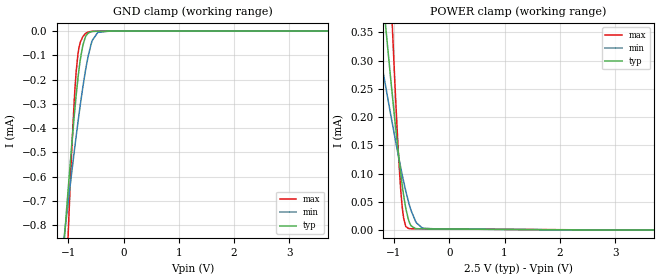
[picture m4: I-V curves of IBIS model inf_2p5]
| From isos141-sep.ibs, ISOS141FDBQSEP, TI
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|   inf_2p5 Model
[Model]   inf_2p5
Model_type   Input
Vinl = 0.75
Vinh = 1.75
|   typ   min   max
|   (nom PVT)   (fast PVT)   (slow PVT)
C_comp   3.281e-15   3.281e-15   3.250e-14
[Model spec]
|subparameter
Vinl   0.75   0.675   0.825
Vinh   1.75   1.575   1.925
| Where nom  PVT is Nominal Process, 2.5V, 27C
|   Fast PVT is Strong Process,  2.75V, -55C
|   Slow PVT is Weak Process,   2.25V, 150C
[Voltage Range]   2.5   2.25   2.75
|Junction Temperature
[Temperature Range]   27   150   -55
[Power Clamp Reference]   2.5   2.25   2.75
[GND Clamp Reference]   0   0   0
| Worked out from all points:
|   GND clamp passes 1 mA (typ) near -1.12 V on its own axis
[GND Clamp]
|   Voltage   I(typ)   I(min)   I(max)
-2.5V     -5.567mA   -3.855mA   -11.2mA
-1.069V   -852.9uA   -838.7uA   -1.235mA
-1.015V   -691.7uA   -732.3uA   -913.4uA
-962.5mV  -540.3uA   -630.7uA   -621.5uA
-880mV    -320.6uA   -475.8uA   -242.7uA
-825mV    -195.8uA   -377.3uA   -96.08uA
-735mV    -57.68uA   -229.6uA   -22.57uA
-641mV    -8.597uA   -105.1uA   -3.988uA
-564mV    -1.717uA   -38.11uA   -871.4nA
-466mV    -415.4nA   -5.597uA   -322nA
-250mV    -166.5nA   -222.7nA   -161.2nA
5V        0A         0A         0A
[POWER Clamp]
|   Voltage   I(typ)   I(min)   I(max)
-2.5V     1.814mA    1.041mA    3.986mA
-1.351V   566.8uA    365.9uA    1.114mA
-1.196V   405.7uA    279uA      742.4uA
-1.053V   260.5uA    200.3uA    408.8uA
-990.2mV  199.2uA    166.7uA    271uA
-924.3mV  138.4uA    132.7uA    141.2uA
-874.8mV  96.55uA    108.3uA    65.49uA
-822.5mV  58.5uA     83.91uA    18.88uA
-740mV    18.48uA    50.19uA    2.683uA
-612.5mV  2.435uA    15.71uA    2.168uA
-486.3mV  1.99uA     3.311uA    2.086uA
5V        0A         0A         0A
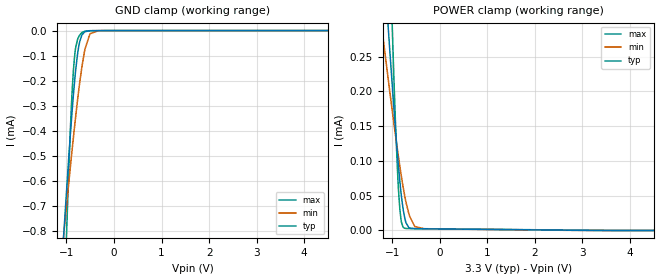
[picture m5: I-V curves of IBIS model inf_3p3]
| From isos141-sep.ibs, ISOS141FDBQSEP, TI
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|   inf_3p3 Model
[Model]   inf_3p3
Model_type   Input
Vinl = 0.99
Vinh = 2.31
|   typ   min   max
|   (nom PVT)   (fast PVT)   (slow PVT)
C_comp   3.281e-15   3.281e-15   3.329e-14
[Model spec]
|subparameter
Vinl   0.99   0.891   1.089
Vinh   2.31   2.079   2.541
| Where nom  PVT is Nominal Process, 3.3V, 27C
|   Fast PVT is Strong Process,  3.63V, -55C
|   Slow PVT is Weak Process,   2.97V, 150C
[Voltage Range]   3.3   2.97   3.63
|Junction Temperature
[Temperature Range]   27   150   -55
[Power Clamp Reference]   3.3   2.97   3.63
[GND Clamp Reference]   0   0   0
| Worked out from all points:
|   GND clamp passes 1 mA (typ) near -1.12 V on its own axis
|   POWER clamp passes 1 mA (typ) near -1.75 V on its own axis
[GND Clamp]
|   Voltage   I(typ)   I(min)   I(max)
-3.3V     -8.284mA   -5.57mA    -16.97mA
-1.076V   -873.6uA   -852.3uA   -1.277mA
-1.002V   -654.2uA   -707.4uA   -840.1uA
-891.3mV  -349uA     -496.6uA   -285.5uA
-853.4mV  -257.3uA   -427.5uA   -158.6uA
-821.7mV  -189.1uA   -371.5uA   -90.58uA
-768.9mV  -98.39uA   -282.7uA   -37.63uA
-719.4mV  -43.62uA   -206.4uA   -17.63uA
-617.1mV  -5.129uA   -80.39uA   -2.416uA
-505.2mV  -641.2nA   -12.81uA   -412.3nA
-330mV    -221.3nA   -470.3nA   -212.8nA
6.6V      0A         0A         0A
[POWER Clamp]
|   Voltage   I(typ)   I(min)   I(max)
-3.3V     2.696mA    1.52mA     6.012mA
-1.242V   453.3uA    304.9uA    851.4uA
-1.198V   407.7uA    280.3uA    746.3uA
-1.049V   257.2uA    198.7uA    400.8uA
-965.9mV  176.8uA    154.6uA    221.3uA
-878.8mV  100.3uA    110.8uA    71.18uA
-842.5mV  72.63uA    93.56uA    33uA
-805.2mV  48.41uA    76.82uA    11.74uA
-737.2mV  18.14uA    49.73uA    3.193uA
-526mV    2.561uA    5.724uA    2.679uA
-330mV    2.416uA    2.488uA    2.553uA
6.6V      0A         0A         0A
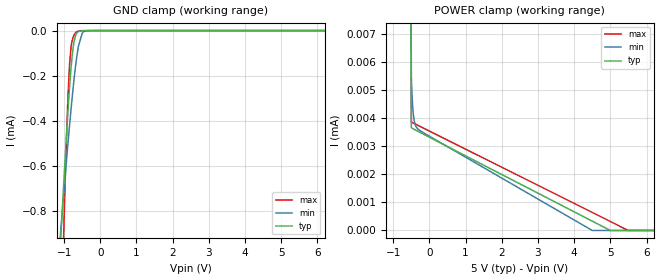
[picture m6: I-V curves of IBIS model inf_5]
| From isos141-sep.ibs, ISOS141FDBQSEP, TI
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|   inf_5 Model
[Model]   inf_5
Model_type   Input
Vinl = 1.5
Vinh = 3.5
|   typ   min   max
|   (nom PVT)   (fast PVT)   (slow PVT)
C_comp   3.281e-15   3.281e-15   3.455e-14
[Model spec]
|subparameter
Vinl   1.5   1.35   1.65
Vinh   3.5   3.15   3.85
| Where nom  PVT is Nominal Process, 5V, 27C
|   Fast PVT is Strong Process,  5.5V, -55C
|   Slow PVT is Weak Process,   4.5V, 150C
[Voltage Range]   5   4.5   5.5
|Junction Temperature
[Temperature Range]   27   150   -55
[Power Clamp Reference]   5   4.5   5.5
[GND Clamp Reference]   0   0   0
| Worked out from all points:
|   GND clamp passes 1 mA (typ) near -1.12 V on its own axis
[GND Clamp]
|   Voltage   I(typ)   I(min)   I(max)
-5V       -13.99mA   -9.044mA   -29.25mA
-1.112V   -984.3uA   -924.5uA   -1.502mA
-1.062V   -831.8uA   -824.9uA   -1.192mA
-974mV    -572.9uA   -652.8uA   -683.2uA
-908mV    -391.9uA   -527.5uA   -354.9uA
-850mV    -249.6uA   -421.5uA   -149.8uA
-809mV    -164.5uA   -349.6uA   -72.24uA
-740mV    -62.8uA    -237.2uA   -24.38uA
-608mV    -4.229uA   -71.85uA   -2.005uA
-500mV    -598.4nA   -11.5uA    -395.2nA
-347mV    -233.9nA   -591nA     -223.9nA
10V       0A         0A         0A
[POWER Clamp]
|   Voltage   I(typ)   I(min)   I(max)
-5V       185.5mA    66.86mA    305.6mA
-1.007V   217uA      177.2uA    308.5uA
-500mV    3.667uA    5.488uA    3.869uA
-486.5mV  3.656uA    5.003uA    3.86uA
-468.5mV  3.642uA    4.538uA    3.848uA
-428mV    3.613uA    3.98uA     3.822uA
-374mV    3.577uA    3.716uA    3.787uA
-279.5mV  3.514uA    3.578uA    3.726uA
4.5V      333.1nA    0A         645nA
5.005V    0A         0A         319.1nA
5.49V     0A         0A         0A
10V       0A         0A         0A
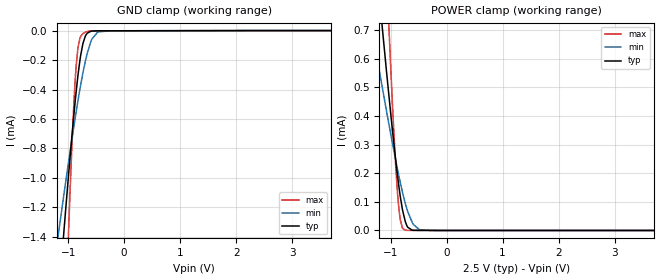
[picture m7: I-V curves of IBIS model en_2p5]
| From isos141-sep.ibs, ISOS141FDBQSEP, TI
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|   en_2p5 Model
[Model]   en_2p5
Model_type   Input
Vinl = 0.75
Vinh = 1.75
|   typ   min   max
|   (nom PVT)   (fast PVT)   (slow PVT)
C_comp   3.303e-15   3.281e-15   1.151e-13
[Model spec]
|subparameter
Vinl   0.75   0.675   0.825
Vinh   1.75   1.575   1.925
| Where nom  PVT is Nominal Process, 2.5V, 27C
|   Fast PVT is Strong Process,  2.75V, -55C
|   Slow PVT is Weak Process,   2.25V, 150C
[Voltage Range]   2.5   2.25   2.75
|Ambient Temperature   25   125   -55
|Junction Temperature
[Temperature Range]   27   150   -55
[Power Clamp Reference]   2.5   2.25   2.75
[GND Clamp Reference]   0   0   0
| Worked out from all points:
|   GND clamp passes 1 mA (typ) near -1.00 V on its own axis
|   POWER clamp passes 1 mA (typ) near -1.29 V on its own axis
[GND Clamp]
|   Voltage   I(typ)   I(min)   I(max)
-2.5V     -8.647mA   -5.195mA   -19.82mA
-1.224V   -2.083mA   -1.519mA   -3.979mA
-1.065V   -1.316mA   -1.086mA   -2.148mA
-1.001V   -1.021mA   -917uA     -1.46mA
-891.2mV  -548.7uA   -636.9uA   -451.9uA
-857.5mV  -419.8uA   -554.9uA   -246.1uA
-825.3mV  -308.5uA   -479.2uA   -120.6uA
-789.5mV  -203.1uA   -398.8uA   -52.86uA
-691mV    -36.17uA   -205.8uA   -10.4uA
-575mV    -3.575uA   -57.61uA   -2.24uA
-250mV    -1.373uA   -1.462uA   -1.451uA
5V        0A         0A         0A
[POWER Clamp]
|   Voltage   I(typ)   I(min)   I(max)
-2.5V     3.622mA    2.076mA    7.967mA
-1.351V   1.129mA    727.2uA    2.224mA
-1.196V   807.1uA    553.5uA    1.48mA
-1.053V   516.7uA    396.2uA    813.3uA
-990.2mV  394.3uA    329.2uA    537.7uA
-924.3mV  272.7uA    261.2uA    278.2uA
-874.8mV  189uA      212.4uA    126.7uA
-822.5mV  113uA      163.7uA    33.56uA
-740mV    33.03uA    96.34uA    1.225uA
-612.5mV  1.036uA    27.5uA     297.8nA
-486.3mV  250nA      2.81uA     235.3nA
5V        0A         0A         0A
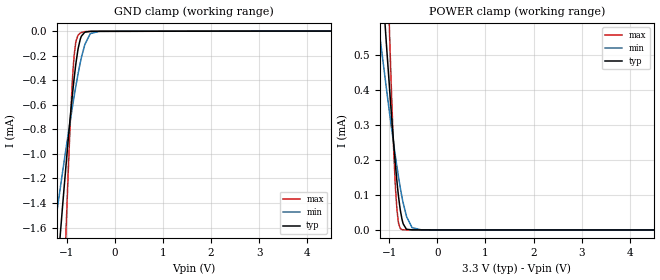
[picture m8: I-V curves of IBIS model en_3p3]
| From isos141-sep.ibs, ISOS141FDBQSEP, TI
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|   en_3p3 Model
[Model]   en_3p3
Model_type   Input
Vinl = 0.99
Vinh = 2.31
|   typ   min   max
|   (nom PVT)   (fast PVT)   (slow PVT)
C_comp   3.303e-15   3.281e-15   1.158e-13
[Model spec]
|subparameter
Vinl   0.99   0.891   1.089
Vinh   2.31   2.079   2.541
| Where nom  PVT is Nominal Process, 3.3V, 27C
|   Fast PVT is Strong Process,  3.63V, -55C
|   Slow PVT is Weak Process,   2.97V, 150C
[Voltage Range]   3.3   2.97   3.63
|Ambient Temperature   25   125   -55
|Junction Temperature
[Temperature Range]   27   150   -55
[Power Clamp Reference]   3.3   2.97   3.63
[GND Clamp Reference]   0   0   0
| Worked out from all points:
|   GND clamp passes 1 mA (typ) near -1.00 V on its own axis
|   POWER clamp passes 1 mA (typ) near -1.29 V on its own axis
[GND Clamp]
|   Voltage   I(typ)   I(min)   I(max)
-3.3V     -12.85mA   -7.552mA   -29.96mA
-1.251V   -2.215mA   -1.593mA   -4.295mA
-1.213V   -2.028mA   -1.488mA   -3.846mA
-1.063V   -1.305mA   -1.079mA   -2.122mA
-980.4mV  -927.6uA   -862.8uA   -1.246mA
-926mV    -691uA     -723.5uA   -729.1uA
-849.8mV  -392.1uA   -536.5uA   -209.7uA
-808.2mV  -255.7uA   -440.3uA   -80.89uA
-697.3mV  -41.71uA   -216.6uA   -11.76uA
-511.2mV  -2.293uA   -20.49uA   -2.098uA
-330mV    -1.815uA   -2.199uA   -1.916uA
6.6V      0A         0A         0A
[POWER Clamp]
|   Voltage   I(typ)   I(min)   I(max)
-3.3V     5.384mA    3.032mA    12.02mA
-1.242V   901.1uA    604.2uA    1.697mA
-1.198V   810uA      555uA      1.487mA
-1.049V   509.1uA    392uA      796uA
-965.9mV  348.5uA    303.8uA    437.1uA
-878.8mV  195.5uA    216.3uA    137uA
-842.5mV  140.2uA    181.9uA    60.64uA
-805.2mV  91.77uA    148.5uA    18.16uA
-737.2mV  31.27uA    94.34uA    1.112uA
-526mV    293.6nA    6.522uA    254.6nA
-330mV    164.9nA    232nA      159.7nA
6.6V      0A         0A         0A
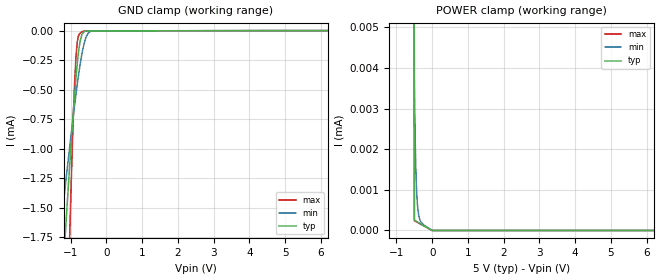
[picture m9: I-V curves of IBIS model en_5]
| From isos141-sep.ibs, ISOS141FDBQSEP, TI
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|   en_5 Model
[Model]   en_5
Model_type   Input
Vinl = 1.5
Vinh = 3.5
|   typ   min   max
|   (nom PVT)   (fast PVT)   (slow PVT)
C_comp   3.303e-15   3.281e-15   1.164e-13
[Model spec]
|subparameter
Vinl   1.5   1.35   1.65
Vinh   3.5   3.15   3.85
| Where nom  PVT is Nominal Process, 5V, 27C
|   Fast PVT is Strong Process,  5.5V, -55C
|   Slow PVT is Weak Process,   4.5V, 150C
[Voltage Range]   5   4.5   5.5
|Ambient Temperature   25   125   -55
|Junction Temperature
[Temperature Range]   27   150   -55
[Power Clamp Reference]   5   4.5   5.5
[GND Clamp Reference]   0   0   0
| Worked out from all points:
|   GND clamp passes 1 mA (typ) near -1.00 V on its own axis
[GND Clamp]
|   Voltage   I(typ)   I(min)   I(max)
-5V       -21.84mA   -12.59mA   -51.61mA
-1.304V   -2.48mA    -1.741mA   -4.932mA
-1.155V   -1.749mA   -1.331mA   -3.177mA
-1.128V   -1.616mA   -1.256mA   -2.86mA
-1.029V   -1.148mA   -990.1uA   -1.755mA
-927.5mV  -697.6uA   -727.4uA   -742.8uA
-855mV    -411.2uA   -549.1uA   -234.7uA
-790mV    -205uA     -400.1uA   -54.24uA
-685mV    -32.64uA   -196.1uA   -10.51uA
-567.5mV  -4.417uA   -52.27uA   -3.419uA
-369.5mV  -2.688uA   -3.564uA   -2.84uA
10V       0A         0A         0A
[POWER Clamp]
|   Voltage   I(typ)   I(min)   I(max)
-5V       371.1mA    133.7mA    611.2mA
-1.007V   426.4uA    346.8uA    609.2uA
-500mV    261.7nA    3.784uA    242nA
-491mV    253.9nA    3.115uA    237.6nA
-482mV    247nA      2.562uA    233.3nA
-473mV    240.7nA    2.107uA    228.9nA
-460mV    232.6nA    1.595uA    222.6nA
-432.5mV  217.1nA    909.5nA    209.3nA
-392mV    196.1nA    454.6nA    189.8nA
-306.5mV  153.2nA    197.5nA    148.4nA
-500uV    0A         0A         0A
10V       0A         0A         0A
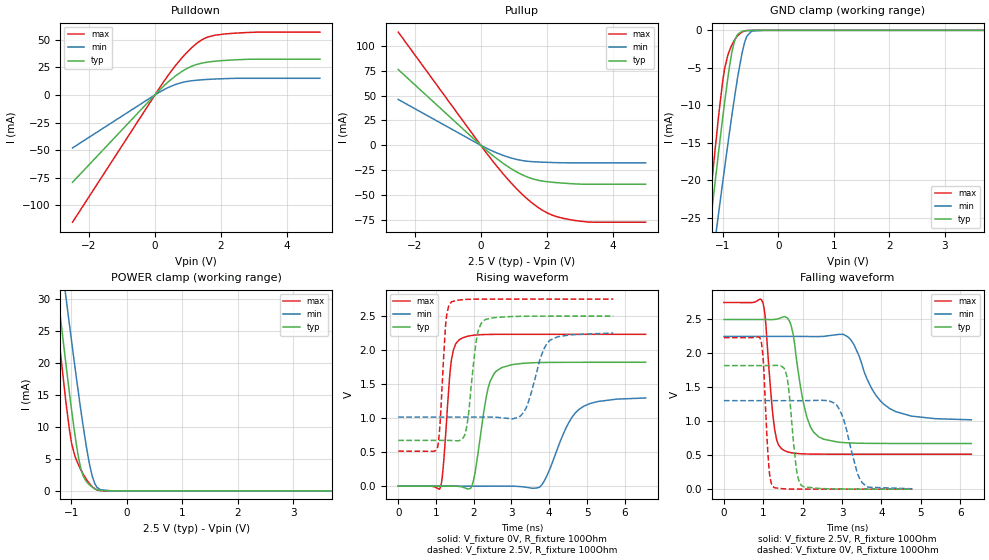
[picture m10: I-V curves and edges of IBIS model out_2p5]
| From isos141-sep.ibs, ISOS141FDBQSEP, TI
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|   out_2p5 Model
[Model]   out_2p5
Model_type   3-state
Polarity   Inverting
Vmeas = 1.25
Vref = 0
Cref = 15pF
Rref = 100
|   typ   min   max
|   (nom PVT)   (fast PVT)   (slow PVT)
C_comp   1.027e-12   9.377e-13   1.105e-12
| Where nom  PVT is Nominal Process, 2.5V, 27C
|   Fast PVT is Strong Process,  2.75V, -55C
|   Slow PVT is Weak Process,   2.25V, 150C
[Voltage Range]   2.5   2.25   2.75
|Ambient Temperature   25   125   -55
|Junction Temperature
[Temperature Range]   27   150   -55
[Pullup Reference]   2.5   2.25   2.75
[Pulldown Reference]   0   0   0
[Power Clamp Reference]   2.5   2.25   2.75
[GND Clamp Reference]   0   0   0
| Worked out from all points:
|   slope of the pulldown table from 0 to 0.375 V, typ, clamps not added: 34 ohm
|   slope of the pullup table from 0 to 0.375 V, typ, clamps not added: 35.4 ohm
|   GND clamp passes 1 mA (typ) near -0.76 V on its own axis
|   POWER clamp passes 1 mA (typ) near -0.68 V on its own axis
|   falling waveform, V_fixture 2.5V, R_fixture 100Ohm: 20-80 % time 324ps typ, 633ps min, 191ps max; typ from 2.5 V to 0.673 V
|   rising waveform, V_fixture 0V, R_fixture 100Ohm: 20-80 % time 307ps typ, 615ps min, 178ps max; typ from 0 V to 1.82 V
|   rising waveform, V_fixture 2.5V, R_fixture 100Ohm: 20-80 % time 210ps typ, 390ps min, 134ps max; typ from 0.673 V to 2.5 V
|   falling waveform, V_fixture 0V, R_fixture 100Ohm: 20-80 % time 178ps typ, 345ps min, 117ps max; typ from 1.82 V to 0 V
[Pulldown]
|   Voltage   I(typ)   I(min)   I(max)
-2.5V     -79.05mA   -47.97mA   -115.1mA
242.5mV   7.369mA    4.254mA    10.99mA
604.8mV   16.75mA    9.164mA    25.83mA
786.3mV   20.6mA     10.9mA     32.43mA
1.1V      25.7mA     12.7mA     42.29mA
1.292V    27.74mA    13.31mA    47.16mA
1.408V    28.6mA     13.59mA    49.53mA
1.631V    29.75mA    14.02mA    52.54mA
2.148V    31.19mA    14.7mA     55.16mA
3.105V    32.21mA    14.98mA    56.72mA
5V        32.21mA    14.98mA    56.75mA
[GND Clamp]
|   Voltage   I(typ)   I(min)   I(max)
-2.5V     -113.8mA   -109.3mA   -126.7mA
-1.327V   -32.82mA   -39.06mA   -30.54mA
-1.16V    -21.76mA   -29.34mA   -17.63mA
-1.073V   -16.17mA   -24.36mA   -11.36mA
-960mV    -9.309mA   -18.06mA   -4.938mA
-871mV    -4.546mA   -13.26mA   -2.575mA
-805mV    -1.936mA   -9.853mA   -1.543mA
-742.5mV  -678.4uA   -6.825mA   -835.1uA
-655mV    -148uA     -3.167mA   -231.5uA
-565mV    -24.88uA   -787.3uA   -32.49uA
-475mV    -3.219uA   -94.87uA   -2.89uA
5V        0A         0A         0A
[Pullup]
|   Voltage   I(typ)   I(min)   I(max)
-2.5V     76.08mA    46.03mA    113.8mA
0V        0A         0A         0A
350.8mV   -9.946mA   -5.734mA   -15.38mA
665mV     -17.88mA   -10.02mA   -28.2mA
1.061V    -26.29mA   -14.04mA   -42.81mA
1.343V    -30.95mA   -15.79mA   -51.94mA
1.605V    -34.09mA   -16.59mA   -59.28mA
1.905V    -36.18mA   -17.06mA   -66.05mA
2.148V    -37.13mA   -17.34mA   -70mA
2.754V    -38.65mA   -17.71mA   -75.11mA
3.3V      -39.22mA   -17.71mA   -77.31mA
5V        -39.22mA   -17.71mA   -77.36mA
[POWER Clamp]
|   Voltage   I(typ)   I(min)   I(max)
-2.5V     130.5mA    131.5mA    137.5mA
-1.331V   37.45mA    46.69mA    32.98mA
-1.194V   27mA       37.02mA    21.48mA
-1.096V   19.79mA    30.25mA    13.84mA
-984.8mV  12.01mA    22.71mA    7.082mA
-912.5mV  7.491mA    17.96mA    4.93mA
-833.5mV  3.695mA    12.97mA    3.404mA
-782.5mV  2.286mA    9.916mA    2.578mA
-667.5mV  905.1uA    3.994mA    1.088mA
-539.3mV  198.3uA    596.8uA    170.5uA
-250mV    142.1nA    1.582uA    12.72nA
5V        0A         0A         0A
[Ramp]
R_load = 100
|   typ   min   max
dV/dt_r   1.0926/3.05799e-10   0.781809/6.18175e-10   1.33922/1.76792e-10
dV/dt_f   1.09612/3.21737e-10   0.740101/6.33785e-10   1.34089/1.89159e-10
[Falling Waveform]
V_fixture = 2.5V
V_fixture_min = 2.25V
V_fixture_max = 2.75V
R_fixture = 100Ohm
|   Time   V(typ)   V(min)   V(max)
0s        2.5V       2.25V      2.75V
980ps     2.5V       2.25V      2.76V
1.286ns   2.501V     2.25V      890.3mV
1.528ns   2.543V     2.25V      570.3mV
1.718ns   2.385V     2.25V      536.1mV
2.106ns   1.061V     2.25V      518.2mV
2.4ns     774.3mV    2.249V     515.8mV
3.212ns   680.8mV    2.208V     515.2mV
4.206ns   673.5mV    1.189V     515.2mV
6.284ns   673.1mV    1.022V     515.2mV
[Rising Waveform]
V_fixture = 0V
V_fixture_min = 0V
V_fixture_max = 0V
R_fixture = 100Ohm
|   Time   V(typ)   V(min)   V(max)
0s        2.759nV    92.09nV    1.558nV
1.108ns   -49.93uV   25.48nV    -28.41mV
1.41ns    984.8uV    875.7nV    1.858V
1.61ns    -3.002mV   3.634uV    2.149V
1.962ns   21.52mV    -16.69uV   2.216V
2.34ns    1.338V     -18.47uV   2.229V
2.596ns   1.691V     495.7uV    2.231V
3.742ns   1.817V     -15.19mV   2.232V
4.912ns   1.821V     1.175V     2.232V
6.554ns   1.821V     1.297V     2.232V
[Rising Waveform]
V_fixture = 2.5V
V_fixture_min = 2.25V
V_fixture_max = 2.75V
R_fixture = 100Ohm
|   Time   V(typ)   V(min)   V(max)
0s        673.1mV    1.016V     515.1mV
1.042ns   673.1mV    1.016V     569.3mV
1.262ns   673.3mV    1.016V     2.408V
1.414ns   671.2mV    1.016V     2.711V
1.786ns   800.7mV    1.016V     2.744V
2.074ns   2.166V     1.016V     2.749V
2.23ns    2.416V     1.016V     2.749V
3.266ns   2.497V     1.048V     2.75V
4.012ns   2.5V       2.143V     2.75V
5.698ns   2.5V       2.25V      2.75V
[Falling Waveform]
V_fixture = 0V
V_fixture_min = 0V
V_fixture_max = 0V
R_fixture = 100Ohm
|   Time   V(typ)   V(min)   V(max)
0s        1.821V     1.304V     2.232V
936ps     1.821V     1.304V     2.195V
1.146ns   1.821V     1.304V     295.8mV
1.23ns    1.822V     1.304V     45.6mV
1.606ns   1.645V     1.304V     3.087mV
1.84ns    296.4mV    1.304V     656.2uV
1.97ns    52.25mV    1.304V     261.7uV
2.862ns   3.154mV    1.24V      -4.6uV
3.606ns   514.4uV    47.67mV    -72.66nV
4.784ns   44.2uV     5.601mV    2.782nV
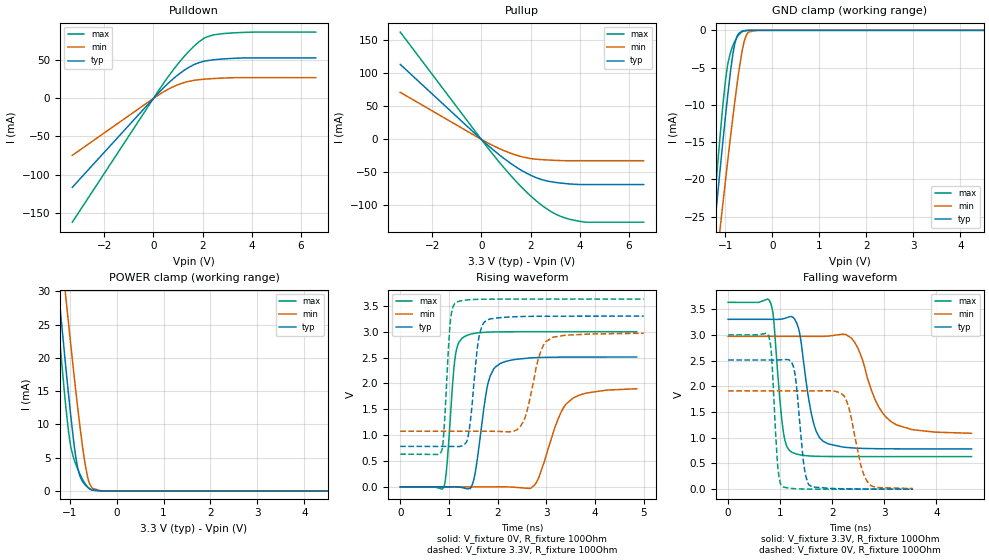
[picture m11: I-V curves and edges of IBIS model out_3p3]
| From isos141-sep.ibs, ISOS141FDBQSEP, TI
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|   out_3p3 Model
[Model]   out_3p3
Model_type   3-state
Polarity   Inverting
Vmeas = 1.65
Vref = 0
Cref = 15pF
Rref = 100
|   typ   min   max
|   (nom PVT)   (fast PVT)   (slow PVT)
C_comp   9.270e-13   8.382e-13   1.039e-12
| Where nom  PVT is Nominal Process, 3.3V, 27C
|   Fast PVT is Strong Process,  3.63V, -55C
|   Slow PVT is Weak Process,   2.97V, 150C
[Voltage Range]   3.3   2.97   3.63
|Ambient Temperature   25   125   -55
|Junction Temperature
[Temperature Range]   27   150   -55
[Pullup Reference]   3.3   2.97   3.63
[Pulldown Reference]   0   0   0
[Power Clamp Reference]   3.3   2.97   3.63
[GND Clamp Reference]   0   0   0
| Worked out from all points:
|   slope of the pulldown table from 0 to 0.495 V, typ, clamps not added: 29.7 ohm
|   slope of the pullup table from 0 to 0.495 V, typ, clamps not added: 30.6 ohm
|   GND clamp passes 1 mA (typ) near -0.76 V on its own axis
|   POWER clamp passes 1 mA (typ) near -0.68 V on its own axis
|   falling waveform, V_fixture 3.3V, R_fixture 100Ohm: 20-80 % time 230ps typ, 430ps min, 149ps max; typ from 3.3 V to 0.782 V
|   rising waveform, V_fixture 0V, R_fixture 100Ohm: 20-80 % time 227ps typ, 427ps min, 140ps max; typ from 0 V to 2.51 V
|   rising waveform, V_fixture 3.3V, R_fixture 100Ohm: 20-80 % time 157ps typ, 277ps min, 107ps max; typ from 0.782 V to 3.3 V
|   falling waveform, V_fixture 0V, R_fixture 100Ohm: 20-80 % time 138ps typ, 238ps min, 95.1ps max; typ from 2.51 V to 0 V
[Pulldown]
|   Voltage   I(typ)   I(min)   I(max)
-3.3V     -116.8mA   -74.8mA    -162.6mA
67.98mV   2.426mA    1.528mA    3.39mA
463mV     15.67mA    9.587mA    22.3mA
860mV     27.32mA    16.13mA    39.76mA
1.256V    37mA       20.88mA    55.31mA
1.633V    44.06mA    23.59mA    68.06mA
1.858V    47.02mA    24.56mA    74.44mA
2.123V    49.2mA     25.37mA    80.1mA
2.414V    50.61mA    26.01mA    83.21mA
2.867V    51.88mA    26.71mA    85.18mA
3.97V     53.09mA    27.18mA    86.97mA
6.6V      53.09mA    27.18mA    87.05mA
[GND Clamp]
|   Voltage   I(typ)   I(min)   I(max)
-3.3V     -170.3mA   -157.8mA   -194.4mA
-1.317V   -32.1mA    -38.42mA   -29.69mA
-1.236V   -26.73mA   -33.72mA   -23.39mA
-1.158V   -21.65mA   -29.24mA   -17.5mA
-1.073V   -16.16mA   -24.35mA   -11.34mA
-953.7mV  -8.946mA   -17.72mA   -4.696mA
-879.4mV  -4.954mA   -13.71mA   -2.735mA
-798.6mV  -1.751mA   -9.533mA   -1.459mA
-656.7mV  -152.7uA   -3.229mA   -238.9uA
-558.7mV  -21.74uA   -692.2uA   -27.8uA
-330mV    -65.89nA   -2.179uA   -17.08nA
6.6V      0A         0A         0A
[Pullup]
|   Voltage   I(typ)   I(min)   I(max)
-3.3V     113.7mA    71.42mA    162.6mA
0V        0A         0A         0A
742.2mV   -23.69mA   -14.11mA   -35.04mA
1.223V    -37.05mA   -21.36mA   -55.86mA
1.648V    -47.2mA    -26.21mA   -72.73mA
2.043V    -54.93mA   -29.12mA   -86.88mA
2.406V    -60.25mA   -30.47mA   -98.28mA
2.824V    -63.99mA   -31.34mA   -109.1mA
3.209V    -65.98mA   -31.95mA   -116.3mA
3.994V    -68.26mA   -32.19mA   -124mA
4.279V    -68.26mA   -32.19mA   -125.3mA
6.6V      -68.26mA   -32.19mA   -125.3mA
[POWER Clamp]
|   Voltage   I(typ)   I(min)   I(max)
-3.3V     196.1mA    190mA      211.9mA
-1.367V   40.17mA    49.19mA    36mA
-1.274V   33.06mA    42.63mA    28.11mA
-1.198V   27.34mA    37.33mA    21.84mA
-1.081V   18.74mA    29.25mA    12.78mA
-973.2mV  11.25mA    21.94mA    6.628mA
-891mV    6.299mA    16.58mA    4.476mA
-825mV    3.399mA    12.45mA    3.258mA
-668.6mV  913.7uA    4.04mA     1.1mA
-592mV    415.6uA    1.476mA    435.3uA
-517.1mV  136.9uA    396.6uA    105.4uA
6.6V      0A         0A         0A
[Ramp]
R_load = 100
|   typ   min   max
dV/dt_r   1.50593/2.2717e-10   1.14438/4.28829e-10   1.79944/1.38256e-10
dV/dt_f   1.51075/2.29121e-10   1.13588/4.29308e-10   1.79824/1.48959e-10
[Falling Waveform]
V_fixture = 3.3V
V_fixture_min = 2.97V
V_fixture_max = 3.63V
R_fixture = 100Ohm
|   Time   V(typ)   V(min)   V(max)
0s        3.3V       2.97V      3.63V
810ps     3.3V       2.97V      3.632V
1.06ns    3.312V     2.97V      1.113V
1.212ns   3.355V     2.97V      725.4mV
1.374ns   3.028V     2.97V      667.8mV
1.642ns   1.272V     2.969V     641.1mV
1.828ns   929.1mV    2.97V      636.1mV
2.428ns   799.2mV    2.857V     633.1mV
3.126ns   784mV      1.314V     633mV
4.674ns   782.1mV    1.085V     632.9mV
[Rising Waveform]
V_fixture = 0V
V_fixture_min = 0V
V_fixture_max = 0V
R_fixture = 100Ohm
|   Time   V(typ)   V(min)   V(max)
0s        3.012nV    81.93nV    1.808nV
902ps     -33.98uV   -43.22nV   5.841mV
1.126ns   1.417mV    2.088uV    2.494V
1.272ns   -13.51mV   4.888uV    2.875V
1.512ns   139.9mV    -29.36uV   2.964V
1.788ns   1.938V     73.47uV    2.99V
1.956ns   2.318V     808.3uV    2.995V
2.754ns   2.497V     31.25mV    2.999V
3.548ns   2.509V     1.715V     2.999V
4.858ns   2.51V      1.897V     2.999V
[Rising Waveform]
V_fixture = 3.3V
V_fixture_min = 2.97V
V_fixture_max = 3.63V
R_fixture = 100Ohm
|   Time   V(typ)   V(min)   V(max)
0s        782mV      1.075V     632.8mV
852ps     782mV      1.075V     699.9mV
1.03ns    782.2mV    1.075V     3.204V
1.164ns   779.9mV    1.075V     3.574V
1.376ns   905.9mV    1.075V     3.613V
1.608ns   2.848V     1.075V     3.625V
1.772ns   3.22V      1.076V     3.628V
2.464ns   3.292V     1.163V     3.63V
3.138ns   3.299V     2.893V     3.63V
5ns       3.3V       2.969V     3.63V
[Falling Waveform]
V_fixture = 0V
V_fixture_min = 0V
V_fixture_max = 0V
R_fixture = 100Ohm
|   Time   V(typ)   V(min)   V(max)
0s        2.51V      1.91V      2.999V
778ps     2.51V      1.91V      2.976V
836ps     2.509V     1.91V      2.555V
954ps     2.51V      1.91V      427.5mV
1.05ns    2.516V     1.91V      44.04mV
1.264ns   2.344V     1.91V      10.22mV
1.556ns   77.23mV    1.909V     1.359mV
2.248ns   6.809mV    1.776V     11.19uV
2.716ns   1.984mV    90.24mV    1.563uV
3.55ns    306.8uV    11.74mV    72.61nV
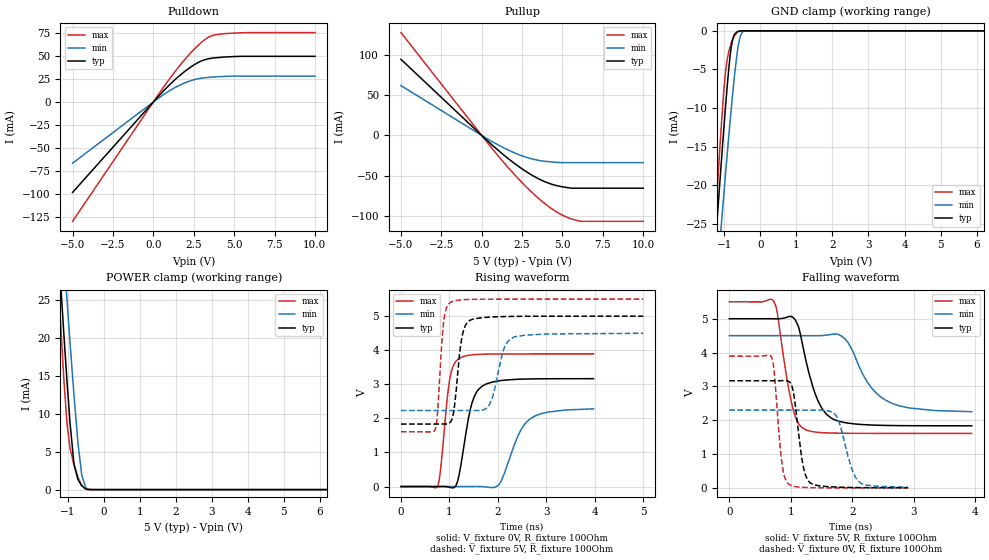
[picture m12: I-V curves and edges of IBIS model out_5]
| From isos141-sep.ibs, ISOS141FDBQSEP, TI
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|   out_5 Model
[Model]   out_5
Model_type   3-state
Polarity   Inverting
Vmeas = 2.5
Vref = 0
Cref = 15pF
Rref = 150
|   typ   min   max
|   (nom PVT)   (fast PVT)   (slow PVT)
C_comp   9.635e-13   9.413e-13   9.787e-13
| Where nom  PVT is Nominal Process, 5V, 27C
|   Fast PVT is Strong Process,  5.5V, -55C
|   Slow PVT is Weak Process,   4.5V, 150C
[Voltage Range]   5   4.5   5.5
|Ambient Temperature   25   125   -55
|Junction Temperature
[Temperature Range]   27   150   -55
[Pullup Reference]   5   4.5   5.5
[Pulldown Reference]   0   0   0
[Power Clamp Reference]   5   4.5   5.5
[GND Clamp Reference]   0   0   0
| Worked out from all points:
|   slope of the pulldown table from 0 to 0.75 V, typ, clamps not added: 52.8 ohm
|   slope of the pullup table from 0 to 0.75 V, typ, clamps not added: 54.8 ohm
|   GND clamp passes 1 mA (typ) near -0.76 V on its own axis
|   POWER clamp passes 1 mA (typ) near -0.67 V on its own axis
|   falling waveform, V_fixture 5V, R_fixture 100Ohm: 20-80 % time 296ps typ, 450ps min, 213ps max; typ from 5 V to 1.83 V
|   rising waveform, V_fixture 0V, R_fixture 100Ohm: 20-80 % time 248ps typ, 401ps min, 165ps max; typ from 0 V to 3.17 V
|   rising waveform, V_fixture 5V, R_fixture 100Ohm: 20-80 % time 143ps typ, 225ps min, 108ps max; typ from 1.83 V to 5 V
|   falling waveform, V_fixture 0V, R_fixture 100Ohm: 20-80 % time 137ps typ, 209ps min, 108ps max; typ from 3.17 V to 0.001 V
[Pulldown]
|   Voltage   I(typ)   I(min)   I(max)
-5V       -97.96mA   -66.29mA   -129.3mA
700mV     13.33mA    8.861mA    17.83mA
1.3V      23.59mA    15.28mA    32.05mA
1.97V     33.54mA    20.95mA    46.53mA
2.663V    41.75mA    24.82mA    59.55mA
3.096V    45.35mA    26.09mA    66.4mA
3.591V    47.4mA     26.94mA    71.64mA
4.416V    48.75mA    27.74mA    74.07mA
5.912V    49.52mA    28.03mA    75.26mA
10V       49.52mA    28.03mA    75.26mA
[GND Clamp]
|   Voltage   I(typ)   I(min)   I(max)
-5V       -291.7mA   -259.7mA   -341.9mA
-1.469V   -42.36mA   -47.38mA   -41.81mA
-1.2V     -24.34mA   -31.61mA   -20.61mA
-1.101V   -17.93mA   -25.94mA   -13.29mA
-1.026V   -13.29mA   -21.76mA   -8.356mA
-940mV    -8.166mA   -16.97mA   -4.222mA
-810.5mV  -2.106mA   -10.13mA   -1.616mA
-737.5mV  -623.1uA   -6.594mA   -788.2uA
-638.5mV  -109.1uA   -2.6mA     -169uA
-558.5mV  -21.67uA   -689.5uA   -27.72uA
-387.5mV  -336nA     -9.718uA   -155.2nA
10V       0A         0A         0A
[Pullup]
|   Voltage   I(typ)   I(min)   I(max)
-5V       94.16mA    61.66mA    127.2mA
100mV     -1.88mA    -1.233mA   -2.555mA
1.3V      -23.12mA   -14.74mA   -31.91mA
2.753V    -44.75mA   -26.97mA   -63.54mA
3.883V    -57.04mA   -31.9mA    -83.94mA
4.338V    -60.4mA    -32.77mA   -90.72mA
4.935V    -63.28mA   -33.6mA    -97.99mA
5.49V     -64.99mA   -33.6mA    -102.8mA
5.984V    -65.24mA   -33.6mA    -105.5mA
10V       -65.24mA   -33.6mA    -106.2mA
[POWER Clamp]
|   Voltage   I(typ)   I(min)   I(max)
-5V       516mA      373mA      669.1mA
-1.535V   53.28mA    61.23mA    50.65mA
-1.128V   22.12mA    32.46mA    16.25mA
-1.101V   20.12mA    30.56mA    14.17mA
-1.018V   14.26mA    24.94mA    8.698mA
-935.5mV  8.857mA    19.46mA    5.475mA
-825mV    3.399mA    12.45mA    3.258mA
-710mV    1.283mA    5.971mA    1.578mA
-608mV    501.8uA    1.883mA    547.9uA
-500mV    100.1uA    287.4uA    70.26uA
-260mV    196.4nA    1.991uA    20.04nA
10V       0A         0A         0A
[Ramp]
R_load = 100
|   typ   min   max
dV/dt_r   1.89956/2.4599e-10   1.37645/4.04325e-10   2.33583/1.64321e-10
dV/dt_f   1.89916/2.94487e-10   1.35805/4.5544e-10   2.3339/2.12977e-10
[Falling Waveform]
V_fixture = 5V
V_fixture_min = 4.5V
V_fixture_max = 5.5V
R_fixture = 100Ohm
|   Time   V(typ)   V(min)   V(max)
0s        5V         4.5V       5.5V
728ps     4.998V     4.5V       5.502V
1.034ns   5.042V     4.5V       2.353V
1.244ns   3.792V     4.499V     1.717V
1.456ns   2.526V     4.498V     1.639V
1.7ns     2.024V     4.547V     1.619V
1.942ns   1.912V     4.275V     1.613V
2.244ns   1.864V     3.137V     1.611V
2.558ns   1.845V     2.578V     1.61V
3.946ns   1.835V     2.251V     1.61V
[Rising Waveform]
V_fixture = 0V
V_fixture_min = 0V
V_fixture_max = 0V
R_fixture = 100Ohm
|   Time   V(typ)   V(min)   V(max)
0s        9.106nV    157nV      6.985nV
762ps     404uV      36.48nV    26.04mV
1.004ns   -22.05mV   9.183uV    3.126V
1.202ns   354.9mV    -77.15uV   3.762V
1.432ns   2.269V     886.7uV    3.858V
1.668ns   2.939V     -1.71mV    3.882V
2.038ns   3.105V     89.55mV    3.891V
2.414ns   3.148V     1.485V     3.893V
2.666ns   3.158V     1.988V     3.893V
3.976ns   3.166V     2.28V      3.893V
[Rising Waveform]
V_fixture = 5V
V_fixture_min = 4.5V
V_fixture_max = 5.5V
R_fixture = 100Ohm
|   Time   V(typ)   V(min)   V(max)
0s        1.834V     2.233V     1.608V
712ps     1.834V     2.233V     1.69V
876ps     1.836V     2.233V     4.762V
1.024ns   1.896V     2.233V     5.406V
1.104ns   2.352V     2.233V     5.449V
1.262ns   4.409V     2.233V     5.48V
1.434ns   4.887V     2.233V     5.492V
1.838ns   4.972V     2.443V     5.499V
2.28ns    4.992V     4.35V      5.5V
5ns       5V         4.498V     5.5V
[Falling Waveform]
V_fixture = 0V
V_fixture_min = 0V
V_fixture_max = 0V
R_fixture = 100Ohm
|   Time   V(typ)   V(min)   V(max)
0s        3.167V     2.298V     3.895V
688ps     3.166V     2.298V     3.863V
866ps     3.17V      2.298V     617.1mV
966ps     3.151V     2.298V     112.7mV
1.044ns   2.82V      2.298V     48.51mV
1.214ns   548.6mV    2.297V     13.33mV
1.318ns   143.8mV    2.297V     6.639mV
1.748ns   23.78mV    2.114V     406.9uV
2.144ns   7.641mV    134.2mV    54.08uV
2.912ns   1.268mV    19.77mV    1.757uV
